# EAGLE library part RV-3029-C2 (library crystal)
Highly accurate, DTCXO Temperature Compensated Real Time Clock / Calendar Module with I2C Interface. Source: Data shhet

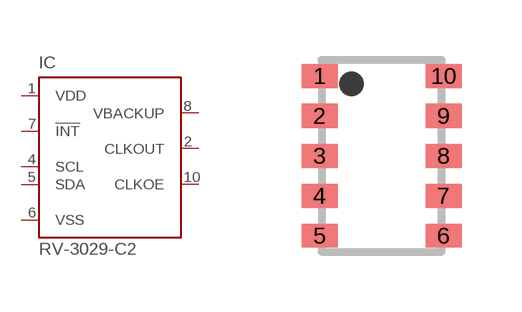
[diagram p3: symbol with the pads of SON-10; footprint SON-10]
Designator prefix IC

## RV-3029-C2  [SON-10]
1  VDD  pwr
2  CLKOUT  out
4  SCL  in
5  SDA
6  VSS  pwr
7  !INT  in
8  VBACKUP  in
10  CLKOE  in

## Footprint SON-10 (pad centres in mm)
SON 10 Pin Source: Data shhet
smd 0.9 x 0.6: 1 -1.55,2; 2 -1.55,1; 3 -1.55,0; 4 -1.55,-1; 5 -1.55,-2; 6 1.55,-2; 7 1.55,-1; 8 1.55,0; 9 1.55,1; 10 1.55,2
